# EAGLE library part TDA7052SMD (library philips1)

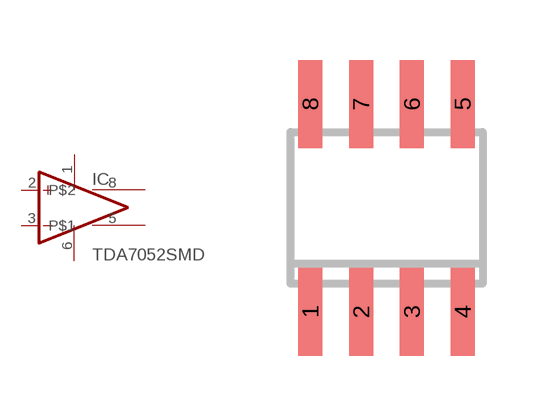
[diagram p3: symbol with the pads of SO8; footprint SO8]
Designator prefix IC

## TDA7052SMD  [SO8]
1  V+  pwr
2  +IN  in
3  -IN  in
5  P$1  out
6  V-  pwr
8  P$2  out

## Footprint SO8 (pad centres in mm)
smd 0.6 x 2.2: 1 -1.905,-2.6; 2 -0.635,-2.6; 3 0.635,-2.6; 4 1.905,-2.6; 5 1.905,2.6; 6 0.635,2.6; 7 -0.635,2.6; 8 -1.905,2.6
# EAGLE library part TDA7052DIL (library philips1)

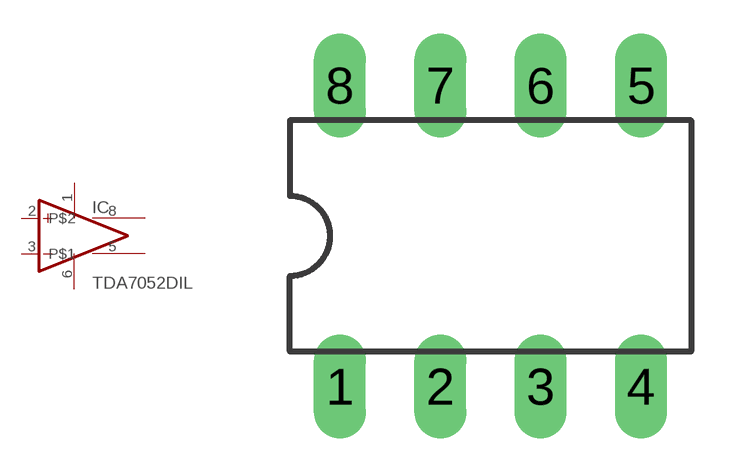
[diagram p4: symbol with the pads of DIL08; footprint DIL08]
Designator prefix IC

## TDA7052DIL  [DIL08]
1  V+  pwr
2  +IN  in
3  -IN  in
5  P$1  out
6  V-  pwr
8  P$2  out

## Footprint DIL08 (pad centres in mm)
Dual In Line Package
drill 0.813 long: 1 -3.81,-3.81; 2 -1.27,-3.81; 3 1.27,-3.81; 4 3.81,-3.81; 5 3.81,3.81; 6 1.27,3.81; 7 -1.27,3.81; 8 -3.81,3.81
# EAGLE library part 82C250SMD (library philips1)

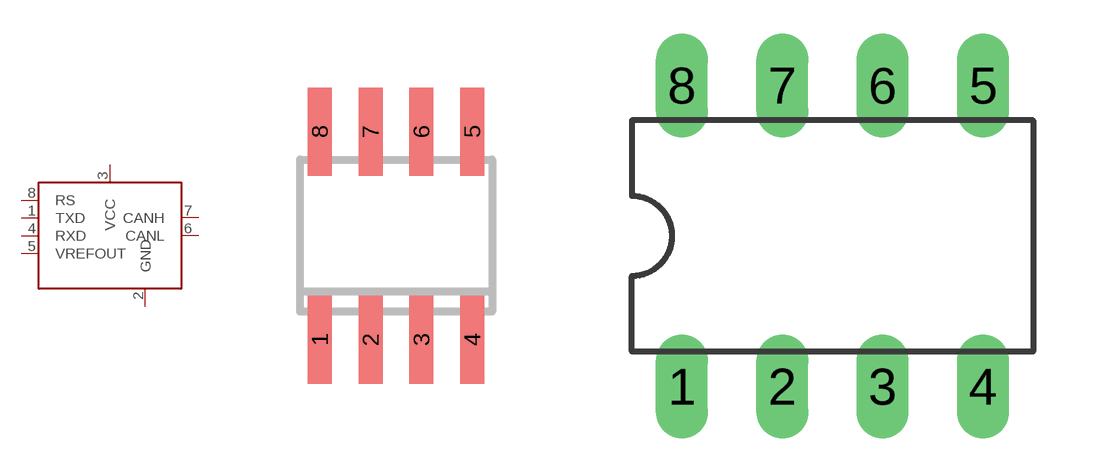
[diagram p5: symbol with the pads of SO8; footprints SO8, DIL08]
Designator prefix IC

## 82C250SMDSMD  [SO8]
1  TXD  in
2  GND  sup
3  VCC  sup
4  RXD  out
5  VREFOUT  out
6  CANL
7  CANH
8  RS  in

## 82C250SMDDIL  [DIL08]
Pads as for SO8

## Footprint SO8 (pad centres in mm)
smd 0.6 x 2.2: 1 -1.905,-2.6; 2 -0.635,-2.6; 3 0.635,-2.6; 4 1.905,-2.6; 5 1.905,2.6; 6 0.635,2.6; 7 -0.635,2.6; 8 -1.905,2.6

## Footprint DIL08 (pad centres in mm)
Dual In Line Package
drill 0.813 long: 1 -3.81,-3.81; 2 -1.27,-3.81; 3 1.27,-3.81; 4 3.81,-3.81; 5 3.81,3.81; 6 1.27,3.81; 7 -1.27,3.81; 8 -3.81,3.81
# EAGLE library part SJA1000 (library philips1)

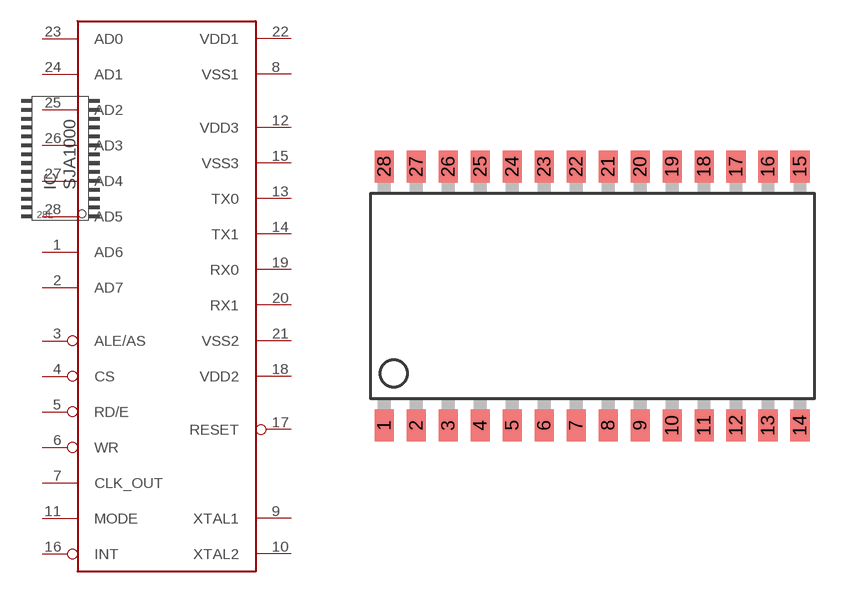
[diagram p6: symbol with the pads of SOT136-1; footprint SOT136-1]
Designator prefix IC

## SJA1000  [SOT136-1]
1  AD6
2  AD7
3  ALE/AS  in
4  CS  in
5  RD/E  in
6  WR  in
7  CLK_OUT  in
8  VSS1  pwr
9  XTAL1  in
10  XTAL2  out
11  MODE  in
12  VDD3  pwr
13  TX0  out
14  TX1  out
15  VSS3  pwr
16  INT  in
17  RESET  in
18  VDD2  pwr
19  RX0  in
20  RX1  in
21  VSS2  pwr
22  VDD1  pwr
23  AD0
24  AD1
25  AD2
26  AD3
27  AD4
28  AD5

## Footprint SOT136-1 (pad centres in mm)
smd 0.762 x 1.27: 1 -8.89,-5.207; 2 -7.62,-5.207; 3 -6.35,-5.207; 4 -5.08,-5.207; 5 -3.81,-5.207; 6 -2.54,-5.207; 7 -1.27,-5.207; 8 0,-5.207; 9 1.27,-5.207; 10 2.54,-5.207; 11 3.81,-5.207; 12 5.08,-5.207; 13 6.35,-5.207; 14 7.62,-5.207; 15 7.62,5.08; 16 6.35,5.08; 17 5.08,5.08; 18 3.81,5.08; 19 2.54,5.08; 20 1.27,5.08; 21 0,5.08; 22 -1.27,5.08; 23 -2.54,5.08; 24 -3.81,5.08; 25 -5.08,5.08; 26 -6.35,5.08; 27 -7.62,5.08; 28 -8.89,5.08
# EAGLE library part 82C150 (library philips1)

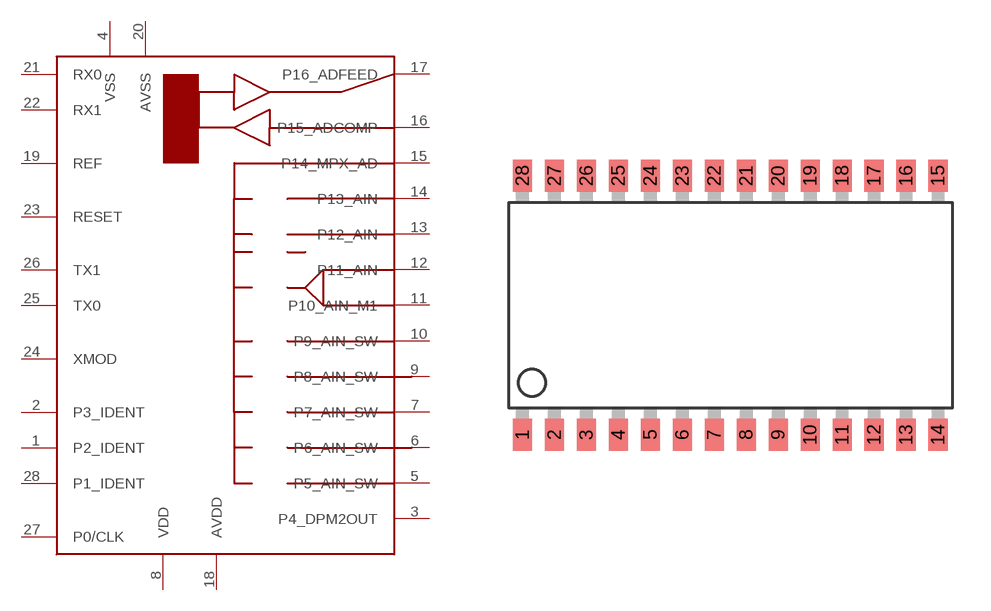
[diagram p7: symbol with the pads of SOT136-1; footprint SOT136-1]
Designator prefix IC

## 82C150  [SOT136-1]
1  P2_IDENT
2  P3_IDENT
3  P4_DPM2OUT
4  VSS  pwr
5  P5_AIN_SW
6  P6_AIN_SW
7  P7_AIN_SW
8  VDD  pwr
9  P8_AIN_SW
10  P9_AIN_SW
11  P10_AIN_M1
12  P11_AIN
13  P12_AIN
14  P13_AIN
15  P14_MPX_AD
16  P15_ADCOMP
17  P16_ADFEED  out
18  AVDD  pwr
19  REF  out
20  AVSS  pwr
21  RX0  in
22  RX1  in
23  RESET  in
24  XMOD  in
25  TX0  out
26  TX1  out
27  P0/CLK
28  P1_IDENT

## Footprint SOT136-1 (pad centres in mm)
smd 0.762 x 1.27: 1 -8.89,-5.207; 2 -7.62,-5.207; 3 -6.35,-5.207; 4 -5.08,-5.207; 5 -3.81,-5.207; 6 -2.54,-5.207; 7 -1.27,-5.207; 8 0,-5.207; 9 1.27,-5.207; 10 2.54,-5.207; 11 3.81,-5.207; 12 5.08,-5.207; 13 6.35,-5.207; 14 7.62,-5.207; 15 7.62,5.08; 16 6.35,5.08; 17 5.08,5.08; 18 3.81,5.08; 19 2.54,5.08; 20 1.27,5.08; 21 0,5.08; 22 -1.27,5.08; 23 -2.54,5.08; 24 -3.81,5.08; 25 -5.08,5.08; 26 -6.35,5.08; 27 -7.62,5.08; 28 -8.89,5.08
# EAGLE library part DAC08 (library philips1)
8bit DAC parallel in, without buslogic 70nssettling time, power supply +- 4,5..18V

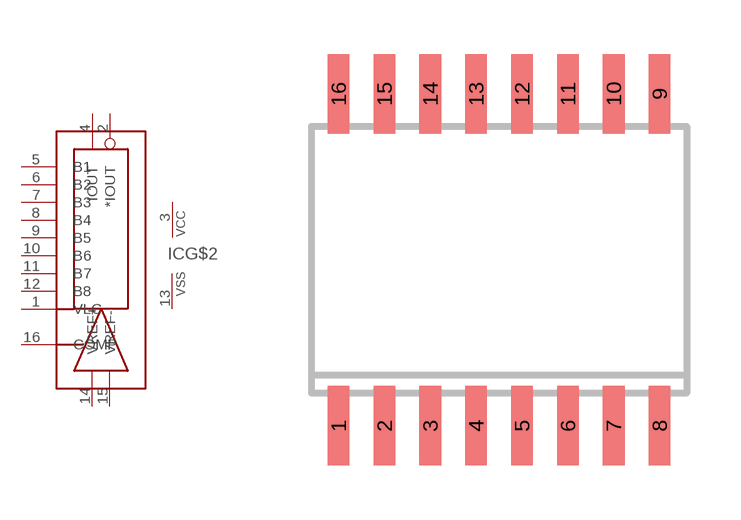
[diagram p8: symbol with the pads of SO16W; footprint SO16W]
Designator prefix IC; gates G$1=DAC08 G$2=VCCVSS

## DAC08SOT16W  [SO16W]
1  G$1:VLC  oc
2  G$1:*IOUT  oc
3  G$2:VCC  pwr
4  G$1:IOUT  oc
5  G$1:B1  in
6  G$1:B2  in
7  G$1:B3  in
8  G$1:B4  in
9  G$1:B5  in
10  G$1:B6  in
11  G$1:B7  in
12  G$1:B8  in
13  G$2:VSS  pwr
14  G$1:VREF+  pas
15  G$1:VREF-  pas
16  G$1:COMP  pas

## Footprint SO16W (pad centres in mm)
smd 0.6 x 2.2: 1 -4.445,-4.6; 2 -3.175,-4.6; 3 -1.905,-4.6; 4 -0.635,-4.6; 5 0.635,-4.6; 6 1.905,-4.6; 7 3.175,-4.6; 8 4.445,-4.6; 9 4.445,4.6; 10 3.175,4.6; 11 1.905,4.6; 12 0.635,4.6; 13 -0.635,4.6; 14 -1.905,4.6; 15 -3.175,4.6; 16 -4.445,4.6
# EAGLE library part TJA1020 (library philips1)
Lin Transiver Vbat 5...27Volt 3,3Volt support no extra supply needed ->www.lin-subbus.org ->www.semiconductor.philips.com/pip/tja1020t

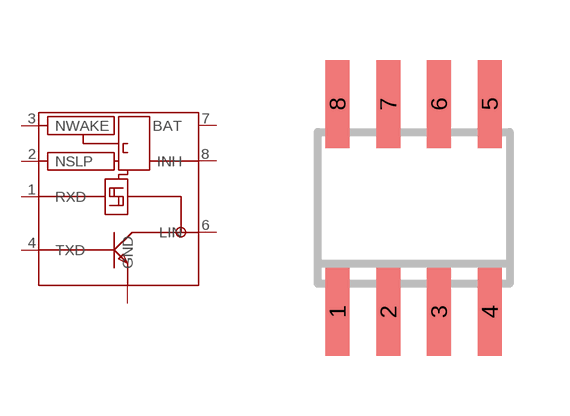
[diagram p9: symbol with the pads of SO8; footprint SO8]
Designator prefix -

## TJA1020SO8  [SO8]
1  RXD  in
2  NSLP  in
3  NWAKE  in
4  TXD  out
5  GND  pwr
6  LIN
7  BAT  pwr
8  INH  out

## Footprint SO8 (pad centres in mm)
smd 0.6 x 2.2: 1 -1.905,-2.6; 2 -0.635,-2.6; 3 0.635,-2.6; 4 1.905,-2.6; 5 1.905,2.6; 6 0.635,2.6; 7 -0.635,2.6; 8 -1.905,2.6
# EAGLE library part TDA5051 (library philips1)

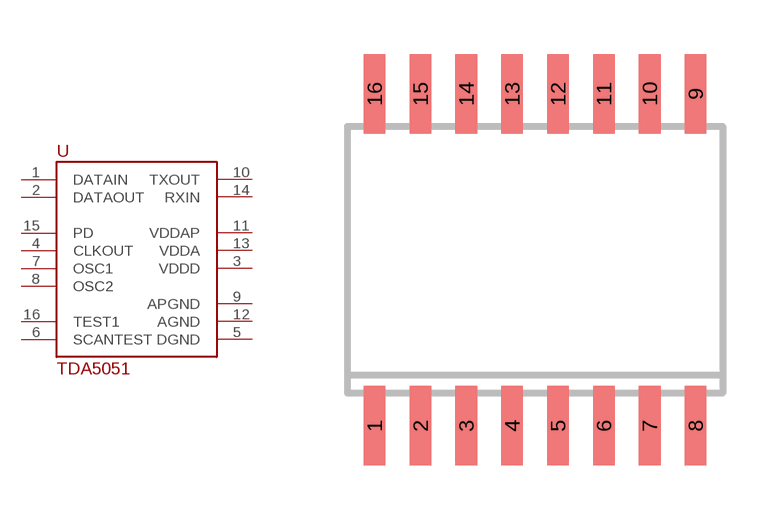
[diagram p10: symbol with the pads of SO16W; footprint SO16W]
Designator prefix -

## TDA5051  [SO16W]
1  DATAIN  in
2  DATAOUT  out
3  VDDD  sup
4  CLKOUT  out
5  DGND  sup
6  SCANTEST
7  OSC1
8  OSC2
9  APGND
10  TXOUT  out
11  VDDAP  sup
12  AGND  sup
13  VDDA  sup
14  RXIN  in
15  PD  in
16  TEST1

## Footprint SO16W (pad centres in mm)
smd 0.6 x 2.2: 1 -4.445,-4.6; 2 -3.175,-4.6; 3 -1.905,-4.6; 4 -0.635,-4.6; 5 0.635,-4.6; 6 1.905,-4.6; 7 3.175,-4.6; 8 4.445,-4.6; 9 4.445,4.6; 10 3.175,4.6; 11 1.905,4.6; 12 0.635,4.6; 13 -0.635,4.6; 14 -1.905,4.6; 15 -3.175,4.6; 16 -4.445,4.6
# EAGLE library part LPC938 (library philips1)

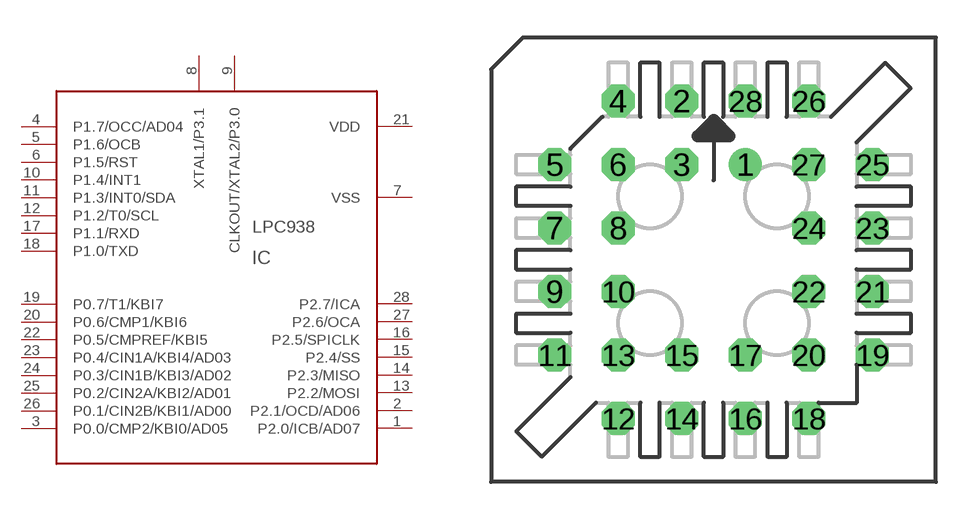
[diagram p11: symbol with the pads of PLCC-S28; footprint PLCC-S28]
Designator prefix IC

## LPC938  [PLCC-S28]
1  P2.0/ICB/AD07
2  P2.1/OCD/AD06
3  P0.0/CMP2/KBI0/AD05
4  P1.7/OCC/AD04
5  P1.6/OCB
6  P1.5/RST
7  VSS
8  XTAL1/P3.1
9  CLKOUT/XTAL2/P3.0
10  P1.4/INT1
11  P1.3/INT0/SDA
12  P1.2/T0/SCL
13  P2.2/MOSI
14  P2.3/MISO
15  P2.4/SS
16  P2.5/SPICLK
17  P1.1/RXD
18  P1.0/TXD
19  P0.7/T1/KBI7
20  P0.6/CMP1/KBI6
21  VDD
22  P0.5/CMPREF/KBI5
23  P0.4/CIN1A/KBI4/AD03
24  P0.3/CIN1B/KBI3/AD02
25  P0.2/CIN2A/KBI2/AD01
26  P0.1/CIN2B/KBI1/AD00
27  P2.6/OCA
28  P2.7/ICA

## Footprint PLCC-S28 (pad centres in mm)
Plastic Leaded Chip Carrier Socked
drill 0.813 round: 1 1.27,3.81
drill 0.813 octagon: 2 -1.27,6.35; 3 -1.27,3.81; 4 -3.81,6.35; 5 -6.35,3.81; 6 -3.81,3.81; 7 -6.35,1.27; 8 -3.81,1.27; 9 -6.35,-1.27; 10 -3.81,-1.27; 11 -6.35,-3.81; 12 -3.81,-6.35; 13 -3.81,-3.81; 14 -1.27,-6.35; 15 -1.27,-3.81; 16 1.27,-6.35; 17 1.27,-3.81; 18 3.81,-6.35; 19 6.35,-3.81; 20 3.81,-3.81; 21 6.35,-1.27; 22 3.81,-1.27; 23 6.35,1.27; 24 3.81,1.27; 25 6.35,3.81; 26 3.81,6.35; 27 3.81,3.81; 28 1.27,6.35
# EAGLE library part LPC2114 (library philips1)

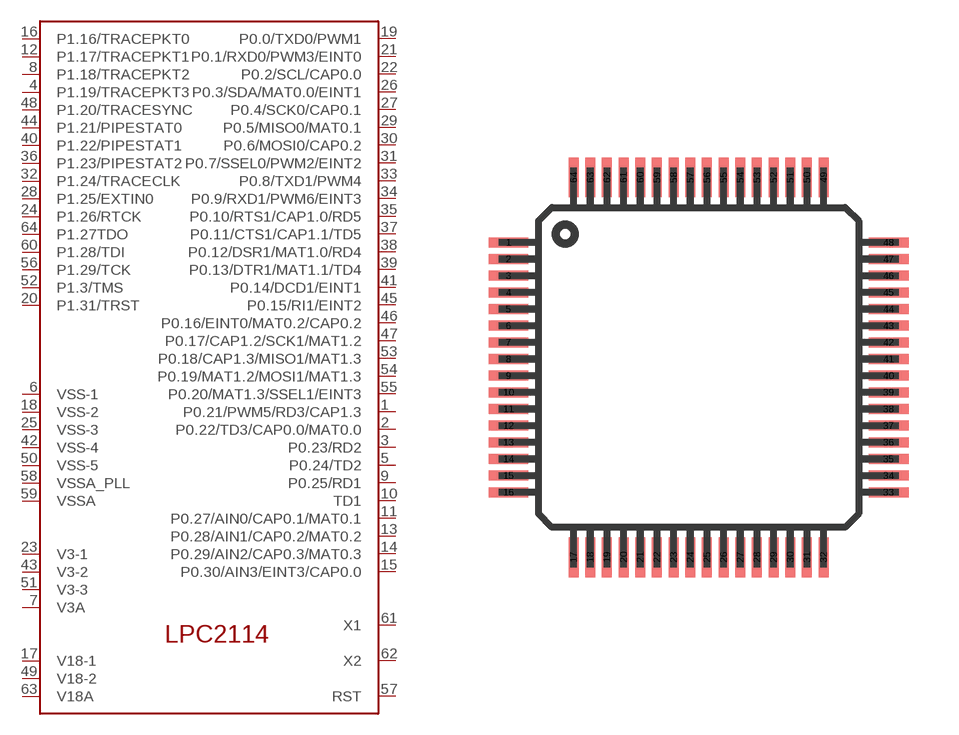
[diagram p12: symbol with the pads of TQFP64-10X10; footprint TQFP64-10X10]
Designator prefix -

## LPC2114  [TQFP64-10X10]
1  P0.21/PWM5/RD3/CAP1.3
2  P0.22/TD3/CAP0.0/MAT0.0
3  P0.23/RD2
4  P1.19/TRACEPKT3
5  P0.24/TD2
6  VSS-1
7  V3A
8  P1.18/TRACEPKT2
9  P0.25/RD1
10  TD1
11  P0.27/AIN0/CAP0.1/MAT0.1
12  P1.17/TRACEPKT1
13  P0.28/AIN1/CAP0.2/MAT0.2
14  P0.29/AIN2/CAP0.3/MAT0.3
15  P0.30/AIN3/EINT3/CAP0.0
16  P1.16/TRACEPKT0
17  V18-1
18  VSS-2
19  P0.0/TXD0/PWM1
20  P1.31/TRST
21  P0.1/RXD0/PWM3/EINT0
22  P0.2/SCL/CAP0.0
23  V3-1
24  P1.26/RTCK
25  VSS-3
26  P0.3/SDA/MAT0.0/EINT1
27  P0.4/SCK0/CAP0.1
28  P1.25/EXTIN0
29  P0.5/MISO0/MAT0.1
30  P0.6/MOSI0/CAP0.2
31  P0.7/SSEL0/PWM2/EINT2
32  P1.24/TRACECLK
33  P0.8/TXD1/PWM4
34  P0.9/RXD1/PWM6/EINT3
35  P0.10/RTS1/CAP1.0/RD5
36  P1.23/PIPESTAT2
37  P0.11/CTS1/CAP1.1/TD5
38  P0.12/DSR1/MAT1.0/RD4
39  P0.13/DTR1/MAT1.1/TD4
40  P1.22/PIPESTAT1
41  P0.14/DCD1/EINT1
42  VSS-4
43  V3-2
44  P1.21/PIPESTAT0
45  P0.15/RI1/EINT2
46  P0.16/EINT0/MAT0.2/CAP0.2
47  P0.17/CAP1.2/SCK1/MAT1.2
48  P1.20/TRACESYNC
49  V18-2
50  VSS-5
51  V3-3
52  P1.3/TMS
53  P0.18/CAP1.3/MISO1/MAT1.3
54  P0.19/MAT1.2/MOSI1/MAT1.3
55  P0.20/MAT1.3/SSEL1/EINT3
56  P1.29/TCK
57  RST
58  VSSA_PLL
59  VSSA
60  P1.28/TDI
61  X1
62  X2
63  V18A
64  P1.27TDO

## Footprint TQFP64-10X10 (pad centres in mm)
Thin Quad Flat Pack package type TQ
smd 1.2 x 0.3: 1 -5.7,3.75; 2 -5.7,3.25; 3 -5.7,2.75; 4 -5.7,2.25; 5 -5.7,1.75; 6 -5.7,1.25; 7 -5.7,0.75; 8 -5.7,0.25; 9 -5.7,-0.25; 10 -5.7,-0.75; 11 -5.7,-1.25; 12 -5.7,-1.75; 13 -5.7,-2.25; 14 -5.7,-2.75; 15 -5.7,-3.25; 16 -5.7,-3.75; 33 5.7,-3.75; 34 5.7,-3.25; 35 5.7,-2.75; 36 5.7,-2.25; 37 5.7,-1.75; 38 5.7,-1.25; 39 5.7,-0.75; 40 5.7,-0.25; 41 5.7,0.25; 42 5.7,0.75; 43 5.7,1.25; 44 5.7,1.75; 45 5.7,2.25; 46 5.7,2.75; 47 5.7,3.25; 48 5.7,3.75
smd 0.3 x 1.2: 17 -3.75,-5.7; 18 -3.25,-5.7; 19 -2.75,-5.7; 20 -2.25,-5.7; 21 -1.75,-5.7; 22 -1.25,-5.7; 23 -0.75,-5.7; 24 -0.25,-5.7; 25 0.25,-5.7; 26 0.75,-5.7; 27 1.25,-5.7; 28 1.75,-5.7; 29 2.25,-5.7; 30 2.75,-5.7; 31 3.25,-5.7; 32 3.75,-5.7; 49 3.75,5.7; 50 3.25,5.7; 51 2.75,5.7; 52 2.25,5.7; 53 1.75,5.7; 54 1.25,5.7; 55 0.75,5.7; 56 0.25,5.7; 57 -0.25,5.7; 58 -0.75,5.7; 59 -1.25,5.7; 60 -1.75,5.7; 61 -2.25,5.7; 62 -2.75,5.7; 63 -3.25,5.7; 64 -3.75,5.7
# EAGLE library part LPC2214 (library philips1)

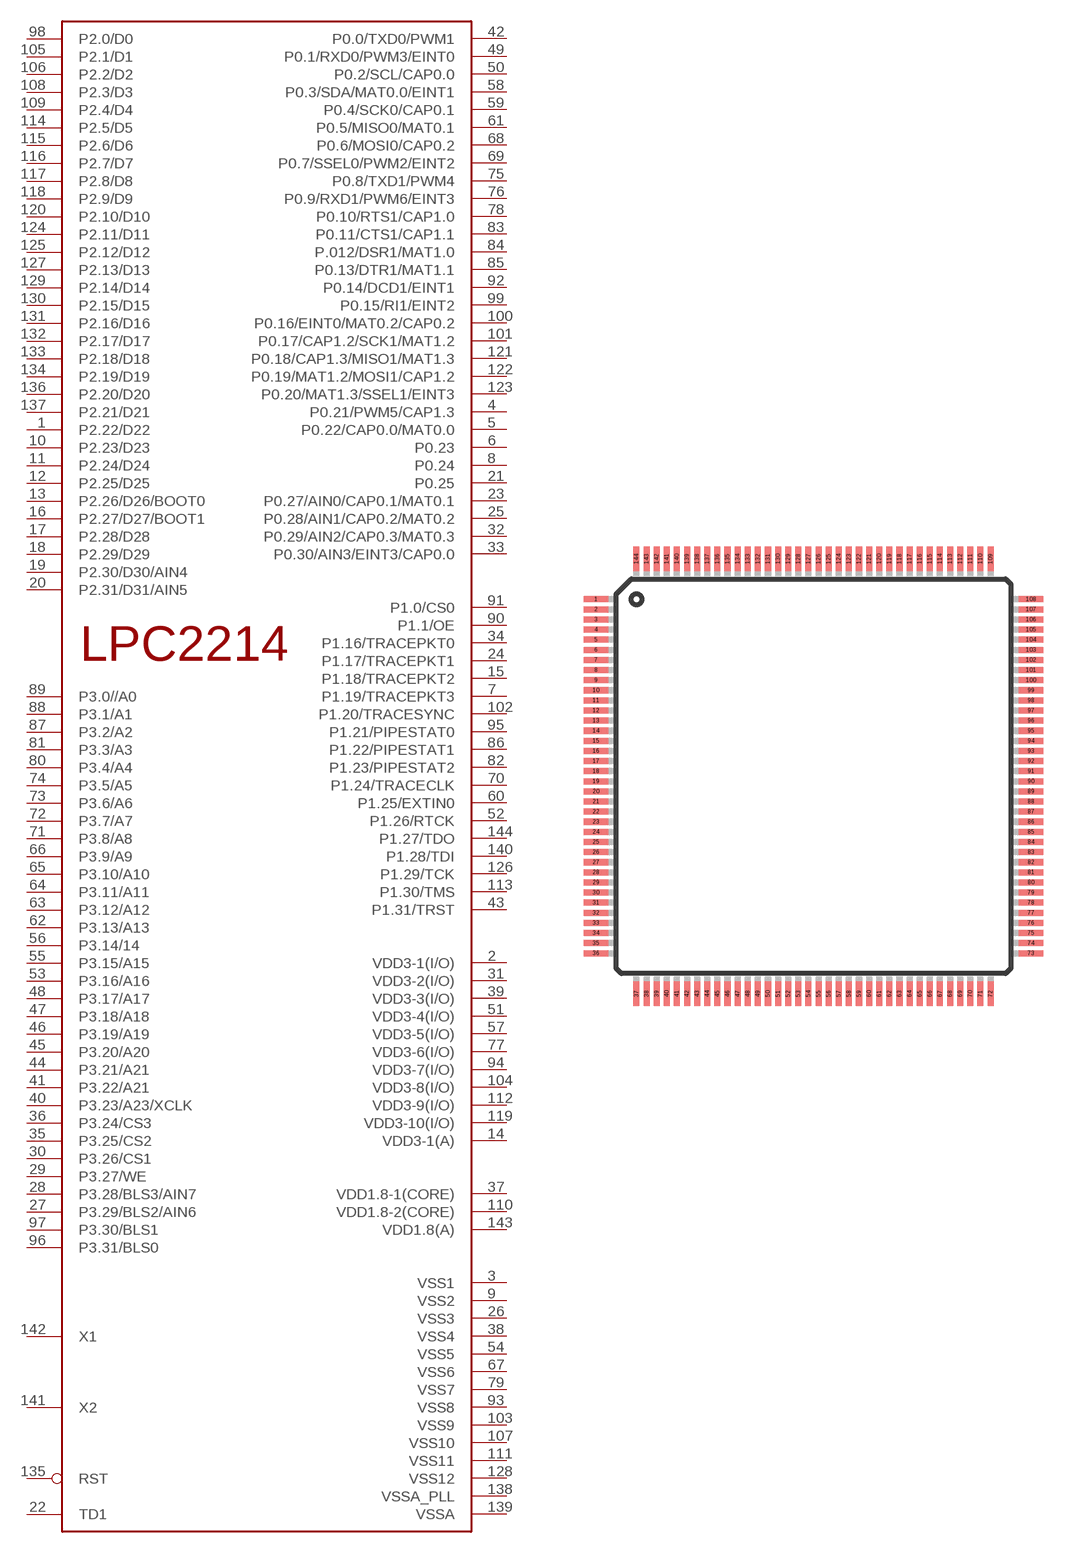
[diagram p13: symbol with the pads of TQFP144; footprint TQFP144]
Designator prefix -

## LPC2214  [TQFP144]
1  P2.22/D22
2  VDD3-1(I/O)
3  VSS1
4  P0.21/PWM5/CAP1.3
5  P0.22/CAP0.0/MAT0.0
6  P0.23
7  P1.19/TRACEPKT3
8  P0.24
9  VSS2
10  P2.23/D23
11  P2.24/D24
12  P2.25/D25
13  P2.26/D26/BOOT0
14  VDD3-1(A)
15  P1.18/TRACEPKT2
16  P2.27/D27/BOOT1
17  P2.28/D28
18  P2.29/D29
19  P2.30/D30/AIN4
20  P2.31/D31/AIN5
21  P0.25
22  TD1
23  P0.27/AIN0/CAP0.1/MAT0.1
24  P1.17/TRACEPKT1
25  P0.28/AIN1/CAP0.2/MAT0.2
26  VSS3
27  P3.29/BLS2/AIN6
28  P3.28/BLS3/AIN7
29  P3.27/WE
30  P3.26/CS1
31  VDD3-2(I/O)
32  P0.29/AIN2/CAP0.3/MAT0.3
33  P0.30/AIN3/EINT3/CAP0.0
34  P1.16/TRACEPKT0
35  P3.25/CS2
36  P3.24/CS3
37  VDD1.8-1(CORE)
38  VSS4
39  VDD3-3(I/O)
40  P3.23/A23/XCLK
41  P3.22/A21
42  P0.0/TXD0/PWM1
43  P1.31/TRST
44  P3.21/A21
45  P3.20/A20
46  P3.19/A19
47  P3.18/A18
48  P3.17/A17
49  P0.1/RXD0/PWM3/EINT0
50  P0.2/SCL/CAP0.0
51  VDD3-4(I/O)
52  P1.26/RTCK
53  P3.16/A16
54  VSS5
55  P3.15/A15
56  P3.14/14
57  VDD3-5(I/O)
58  P0.3/SDA/MAT0.0/EINT1
59  P0.4/SCK0/CAP0.1
60  P1.25/EXTIN0
61  P0.5/MISO0/MAT0.1
62  P3.13/A13
63  P3.12/A12
64  P3.11/A11
65  P3.10/A10
66  P3.9/A9
67  VSS6
68  P0.6/MOSI0/CAP0.2
69  P0.7/SSEL0/PWM2/EINT2
70  P1.24/TRACECLK
71  P3.8/A8
72  P3.7/A7
73  P3.6/A6
74  P3.5/A5
75  P0.8/TXD1/PWM4
76  P0.9/RXD1/PWM6/EINT3
77  VDD3-6(I/O)
78  P0.10/RTS1/CAP1.0
79  VSS7
80  P3.4/A4
81  P3.3/A3
82  P1.23/PIPESTAT2
83  P0.11/CTS1/CAP1.1
84  P.012/DSR1/MAT1.0
85  P0.13/DTR1/MAT1.1
86  P1.22/PIPESTAT1
87  P3.2/A2
88  P3.1/A1
89  P3.0//A0
90  P1.1/OE
91  P1.0/CS0
92  P0.14/DCD1/EINT1
93  VSS8
94  VDD3-7(I/O)
95  P1.21/PIPESTAT0
96  P3.31/BLS0
97  P3.30/BLS1
98  P2.0/D0
99  P0.15/RI1/EINT2
100  P0.16/EINT0/MAT0.2/CAP0.2
101  P0.17/CAP1.2/SCK1/MAT1.2
102  P1.20/TRACESYNC
103  VSS9
104  VDD3-8(I/O)
105  P2.1/D1
106  P2.2/D2
107  VSS10
108  P2.3/D3
109  P2.4/D4
110  VDD1.8-2(CORE)
111  VSS11
112  VDD3-9(I/O)
113  P1.30/TMS
114  P2.5/D5
115  P2.6/D6
116  P2.7/D7
117  P2.8/D8
118  P2.9/D9
119  VDD3-10(I/O)
120  P2.10/D10
121  P0.18/CAP1.3/MISO1/MAT1.3
122  P0.19/MAT1.2/MOSI1/CAP1.2
123  P0.20/MAT1.3/SSEL1/EINT3
124  P2.11/D11
125  P2.12/D12
126  P1.29/TCK
127  P2.13/D13
128  VSS12
129  P2.14/D14
130  P2.15/D15
131  P2.16/D16
132  P2.17/D17
133  P2.18/D18
134  P2.19/D19
135  RST
136  P2.20/D20
137  P2.21/D21
138  VSSA_PLL
139  VSSA
140  P1.28/TDI
141  X2
142  X1
143  VDD1.8(A)
144  P1.27/TDO

## Footprint TQFP144 (pad centres in mm)
THIN QUAD FLAT PACK
smd 1.2 x 0.3: 1 -10.75,8.75; 2 -10.75,8.25; 3 -10.75,7.75; 4 -10.75,7.25; 5 -10.75,6.75; 6 -10.75,6.25; 7 -10.75,5.75; 8 -10.75,5.25; 9 -10.75,4.75; 10 -10.75,4.25; 11 -10.75,3.75; 12 -10.75,3.25; 13 -10.75,2.75; 14 -10.75,2.25; 15 -10.75,1.75; 16 -10.75,1.25; 17 -10.75,0.75; 18 -10.75,0.25; 19 -10.75,-0.25; 20 -10.75,-0.75; 21 -10.75,-1.25; 22 -10.75,-1.75; 23 -10.75,-2.25; 24 -10.75,-2.75; 25 -10.75,-3.25; 26 -10.75,-3.75; 27 -10.75,-4.25; 28 -10.75,-4.75; 29 -10.75,-5.25; 30 -10.75,-5.75; 31 -10.75,-6.25; 32 -10.75,-6.75; 33 -10.75,-7.25; 34 -10.75,-7.75; 35 -10.75,-8.25; 36 -10.75,-8.75; 73 10.75,-8.75; 74 10.75,-8.25; 75 10.75,-7.75; 76 10.75,-7.25; 77 10.75,-6.75; 78 10.75,-6.25; 79 10.75,-5.75; 80 10.75,-5.25; 81 10.75,-4.75; 82 10.75,-4.25; 83 10.75,-3.75; 84 10.75,-3.25; 85 10.75,-2.75; 86 10.75,-2.25; 87 10.75,-1.75; 88 10.75,-1.25; 89 10.75,-0.75; 90 10.75,-0.25; 91 10.75,0.25; 92 10.75,0.75; 93 10.75,1.25; 94 10.75,1.75; 95 10.75,2.25; 96 10.75,2.75; 97 10.75,3.25; 98 10.75,3.75; 99 10.75,4.25; 100 10.75,4.75; 101 10.75,5.25; 102 10.75,5.75; 103 10.75,6.25; 104 10.75,6.75; 105 10.75,7.25; 106 10.75,7.75; 107 10.75,8.25; 108 10.75,8.75
smd 0.3 x 1.2: 37 -8.75,-10.75; 38 -8.25,-10.75; 39 -7.75,-10.75; 40 -7.25,-10.75; 41 -6.75,-10.75; 42 -6.25,-10.75; 43 -5.75,-10.75; 44 -5.25,-10.75; 45 -4.75,-10.75; 46 -4.25,-10.75; 47 -3.75,-10.75; 48 -3.25,-10.75; 49 -2.75,-10.75; 50 -2.25,-10.75; 51 -1.75,-10.75; 52 -1.25,-10.75; 53 -0.75,-10.75; 54 -0.25,-10.75; 55 0.25,-10.75; 56 0.75,-10.75; 57 1.25,-10.75; 58 1.75,-10.75; 59 2.25,-10.75; 60 2.75,-10.75; 61 3.25,-10.75; 62 3.75,-10.75; 63 4.25,-10.75; 64 4.75,-10.75; 65 5.25,-10.75; 66 5.75,-10.75; 67 6.25,-10.75; 68 6.75,-10.75; 69 7.25,-10.75; 70 7.75,-10.75; 71 8.25,-10.75; 72 8.75,-10.75; 109 8.75,10.75; 110 8.25,10.75; 111 7.75,10.75; 112 7.25,10.75; 113 6.75,10.75; 114 6.25,10.75; 115 5.75,10.75; 116 5.25,10.75; 117 4.75,10.75; 118 4.25,10.75; 119 3.75,10.75; 120 3.25,10.75; 121 2.75,10.75; 122 2.25,10.75; 123 1.75,10.75; 124 1.25,10.75; 125 0.75,10.75; 126 0.25,10.75; 127 -0.25,10.75; 128 -0.75,10.75; 129 -1.25,10.75; 130 -1.75,10.75; 131 -2.25,10.75; 132 -2.75,10.75; 133 -3.25,10.75; 134 -3.75,10.75; 135 -4.25,10.75; 136 -4.75,10.75; 137 -5.25,10.75; 138 -5.75,10.75; 139 -6.25,10.75; 140 -6.75,10.75; 141 -7.25,10.75; 142 -7.75,10.75; 143 -8.25,10.75; 144 -8.75,10.75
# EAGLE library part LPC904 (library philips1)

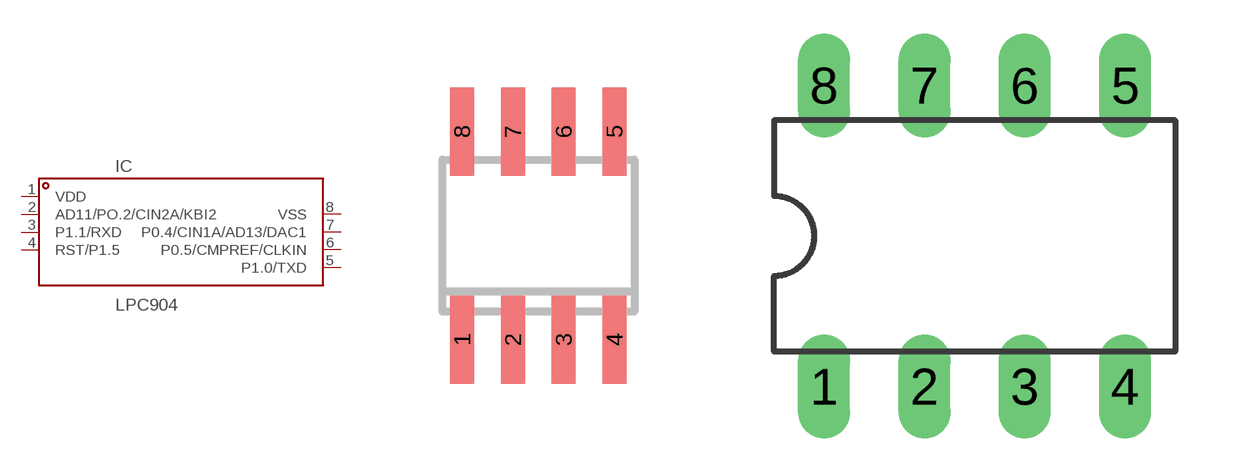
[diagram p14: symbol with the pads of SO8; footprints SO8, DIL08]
Designator prefix IC

## LPC904FD  [SO8]
1  VDD
2  AD11/PO.2/CIN2A/KBI2
3  P1.1/RXD
4  RST/P1.5
5  P1.0/TXD
6  P0.5/CMPREF/CLKIN
7  P0.4/CIN1A/AD13/DAC1
8  VSS

## LPC904FN  [DIL08]
Pads as for SO8

## Footprint SO8 (pad centres in mm)
smd 0.6 x 2.2: 1 -1.905,-2.6; 2 -0.635,-2.6; 3 0.635,-2.6; 4 1.905,-2.6; 5 1.905,2.6; 6 0.635,2.6; 7 -0.635,2.6; 8 -1.905,2.6

## Footprint DIL08 (pad centres in mm)
Dual In Line Package
drill 0.813 long: 1 -3.81,-3.81; 2 -1.27,-3.81; 3 1.27,-3.81; 4 3.81,-3.81; 5 3.81,3.81; 6 1.27,3.81; 7 -1.27,3.81; 8 -3.81,3.81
